VERSION 5.7 ;
  NOWIREEXTENSIONATPIN ON ;
  DIVIDERCHAR "/" ;
  BUSBITCHARS "[]" ;
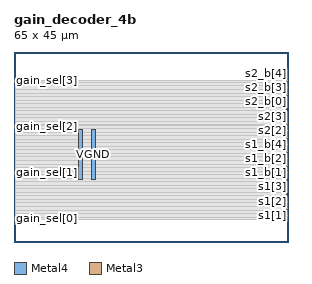
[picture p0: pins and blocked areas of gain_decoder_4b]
MACRO gain_decoder_4b
  CLASS BLOCK ;
  FOREIGN gain_decoder_4b ;
  ORIGIN 0.000 0.000 ;
  SIZE 65.000 BY 45.000 ;
  PIN VGND
    DIRECTION INOUT ;
    USE GROUND ;
    PORT
      LAYER Metal4 ;
        RECT 18.260 14.900 19.260 26.680 ;
    END
  END VGND
  PIN VPWR
    DIRECTION INOUT ;
    USE POWER ;
    PORT
      LAYER Metal4 ;
        RECT 15.260 14.900 16.260 26.680 ;
    END
  END VPWR
  PIN gain_sel[0]
    DIRECTION INPUT ;
    USE SIGNAL ;
    ANTENNAGATEAREA 0.180700 ;
    PORT
      LAYER Metal3 ;
        RECT 0.000 5.260 0.400 5.660 ;
    END
  END gain_sel[0]
  PIN gain_sel[1]
    DIRECTION INPUT ;
    USE SIGNAL ;
    ANTENNAGATEAREA 0.180700 ;
    PORT
      LAYER Metal3 ;
        RECT 0.000 16.180 0.400 16.580 ;
    END
  END gain_sel[1]
  PIN gain_sel[2]
    DIRECTION INPUT ;
    USE SIGNAL ;
    ANTENNAGATEAREA 0.180700 ;
    PORT
      LAYER Metal3 ;
        RECT 0.000 27.100 0.400 27.500 ;
    END
  END gain_sel[2]
  PIN gain_sel[3]
    DIRECTION INPUT ;
    USE SIGNAL ;
    ANTENNAGATEAREA 0.180700 ;
    PORT
      LAYER Metal3 ;
        RECT 0.000 38.020 0.400 38.420 ;
    END
  END gain_sel[3]
  PIN s1[0]
    DIRECTION OUTPUT ;
    USE SIGNAL ;
    ANTENNADIFFAREA 0.708600 ;
    PORT
      LAYER Metal3 ;
        RECT 64.600 6.100 65.000 6.500 ;
    END
  END s1[0]
  PIN s1[1]
    DIRECTION OUTPUT ;
    USE SIGNAL ;
    ANTENNADIFFAREA 0.708600 ;
    PORT
      LAYER Metal3 ;
        RECT 64.600 7.780 65.000 8.180 ;
    END
  END s1[1]
  PIN s1[2]
    DIRECTION OUTPUT ;
    USE SIGNAL ;
    ANTENNADIFFAREA 0.708600 ;
    PORT
      LAYER Metal3 ;
        RECT 64.600 9.460 65.000 9.860 ;
    END
  END s1[2]
  PIN s1[3]
    DIRECTION OUTPUT ;
    USE SIGNAL ;
    ANTENNADIFFAREA 0.708600 ;
    PORT
      LAYER Metal3 ;
        RECT 64.600 11.140 65.000 11.540 ;
    END
  END s1[3]
  PIN s1[4]
    DIRECTION OUTPUT ;
    USE SIGNAL ;
    ANTENNADIFFAREA 0.708600 ;
    PORT
      LAYER Metal3 ;
        RECT 64.600 12.820 65.000 13.220 ;
    END
  END s1[4]
  PIN s1_b[0]
    DIRECTION OUTPUT ;
    USE SIGNAL ;
    ANTENNADIFFAREA 0.708600 ;
    PORT
      LAYER Metal3 ;
        RECT 64.600 14.500 65.000 14.900 ;
    END
  END s1_b[0]
  PIN s1_b[1]
    DIRECTION OUTPUT ;
    USE SIGNAL ;
    ANTENNADIFFAREA 0.708600 ;
    PORT
      LAYER Metal3 ;
        RECT 64.600 16.180 65.000 16.580 ;
    END
  END s1_b[1]
  PIN s1_b[2]
    DIRECTION OUTPUT ;
    USE SIGNAL ;
    ANTENNADIFFAREA 0.708600 ;
    PORT
      LAYER Metal3 ;
        RECT 64.600 17.860 65.000 18.260 ;
    END
  END s1_b[2]
  PIN s1_b[3]
    DIRECTION OUTPUT ;
    USE SIGNAL ;
    ANTENNADIFFAREA 0.708600 ;
    PORT
      LAYER Metal3 ;
        RECT 64.600 19.540 65.000 19.940 ;
    END
  END s1_b[3]
  PIN s1_b[4]
    DIRECTION OUTPUT ;
    USE SIGNAL ;
    ANTENNADIFFAREA 0.708600 ;
    PORT
      LAYER Metal3 ;
        RECT 64.600 21.220 65.000 21.620 ;
    END
  END s1_b[4]
  PIN s2[0]
    DIRECTION OUTPUT ;
    USE SIGNAL ;
    ANTENNADIFFAREA 0.708600 ;
    PORT
      LAYER Metal3 ;
        RECT 64.600 22.900 65.000 23.300 ;
    END
  END s2[0]
  PIN s2[1]
    DIRECTION OUTPUT ;
    USE SIGNAL ;
    ANTENNADIFFAREA 0.708600 ;
    PORT
      LAYER Metal3 ;
        RECT 64.600 24.580 65.000 24.980 ;
    END
  END s2[1]
  PIN s2[2]
    DIRECTION OUTPUT ;
    USE SIGNAL ;
    ANTENNADIFFAREA 0.708600 ;
    PORT
      LAYER Metal3 ;
        RECT 64.600 26.260 65.000 26.660 ;
    END
  END s2[2]
  PIN s2[3]
    DIRECTION OUTPUT ;
    USE SIGNAL ;
    ANTENNADIFFAREA 0.708600 ;
    PORT
      LAYER Metal3 ;
        RECT 64.600 27.940 65.000 28.340 ;
    END
  END s2[3]
  PIN s2[4]
    DIRECTION OUTPUT ;
    USE SIGNAL ;
    ANTENNADIFFAREA 0.708600 ;
    PORT
      LAYER Metal3 ;
        RECT 64.600 29.620 65.000 30.020 ;
    END
  END s2[4]
  PIN s2_b[0]
    DIRECTION OUTPUT ;
    USE SIGNAL ;
    ANTENNADIFFAREA 0.708600 ;
    PORT
      LAYER Metal3 ;
        RECT 64.600 31.300 65.000 31.700 ;
    END
  END s2_b[0]
  PIN s2_b[1]
    DIRECTION OUTPUT ;
    USE SIGNAL ;
    ANTENNADIFFAREA 0.708600 ;
    PORT
      LAYER Metal3 ;
        RECT 64.600 32.980 65.000 33.380 ;
    END
  END s2_b[1]
  PIN s2_b[2]
    DIRECTION OUTPUT ;
    USE SIGNAL ;
    ANTENNADIFFAREA 0.708600 ;
    PORT
      LAYER Metal3 ;
        RECT 64.600 34.660 65.000 35.060 ;
    END
  END s2_b[2]
  PIN s2_b[3]
    DIRECTION OUTPUT ;
    USE SIGNAL ;
    ANTENNADIFFAREA 0.708600 ;
    PORT
      LAYER Metal3 ;
        RECT 64.600 36.340 65.000 36.740 ;
    END
  END s2_b[3]
  PIN s2_b[4]
    DIRECTION OUTPUT ;
    USE SIGNAL ;
    ANTENNADIFFAREA 0.708600 ;
    PORT
      LAYER Metal3 ;
        RECT 64.600 38.020 65.000 38.420 ;
    END
  END s2_b[4]
  OBS
      LAYER GatPoly ;
        RECT 5.760 14.970 59.040 26.610 ;
      LAYER Metal1 ;
        RECT 5.760 14.900 59.040 26.680 ;
      LAYER Metal2 ;
        RECT 6.135 5.315 59.145 38.365 ;
      LAYER Metal3 ;
        RECT 0.610 37.810 64.390 38.320 ;
        RECT 0.400 36.950 64.600 37.810 ;
        RECT 0.400 36.130 64.390 36.950 ;
        RECT 0.400 35.270 64.600 36.130 ;
        RECT 0.400 34.450 64.390 35.270 ;
        RECT 0.400 33.590 64.600 34.450 ;
        RECT 0.400 32.770 64.390 33.590 ;
        RECT 0.400 31.910 64.600 32.770 ;
        RECT 0.400 31.090 64.390 31.910 ;
        RECT 0.400 30.230 64.600 31.090 ;
        RECT 0.400 29.410 64.390 30.230 ;
        RECT 0.400 28.550 64.600 29.410 ;
        RECT 0.400 27.730 64.390 28.550 ;
        RECT 0.400 27.710 64.600 27.730 ;
        RECT 0.610 26.890 64.600 27.710 ;
        RECT 0.400 26.870 64.600 26.890 ;
        RECT 0.400 26.050 64.390 26.870 ;
        RECT 0.400 25.190 64.600 26.050 ;
        RECT 0.400 24.370 64.390 25.190 ;
        RECT 0.400 23.510 64.600 24.370 ;
        RECT 0.400 22.690 64.390 23.510 ;
        RECT 0.400 21.830 64.600 22.690 ;
        RECT 0.400 21.010 64.390 21.830 ;
        RECT 0.400 20.150 64.600 21.010 ;
        RECT 0.400 19.330 64.390 20.150 ;
        RECT 0.400 18.470 64.600 19.330 ;
        RECT 0.400 17.650 64.390 18.470 ;
        RECT 0.400 16.790 64.600 17.650 ;
        RECT 0.610 15.970 64.390 16.790 ;
        RECT 0.400 15.110 64.600 15.970 ;
        RECT 0.400 14.290 64.390 15.110 ;
        RECT 0.400 13.430 64.600 14.290 ;
        RECT 0.400 12.610 64.390 13.430 ;
        RECT 0.400 11.750 64.600 12.610 ;
        RECT 0.400 10.930 64.390 11.750 ;
        RECT 0.400 10.070 64.600 10.930 ;
        RECT 0.400 9.250 64.390 10.070 ;
        RECT 0.400 8.390 64.600 9.250 ;
        RECT 0.400 7.570 64.390 8.390 ;
        RECT 0.400 6.710 64.600 7.570 ;
        RECT 0.400 5.890 64.390 6.710 ;
        RECT 0.400 5.870 64.600 5.890 ;
        RECT 0.610 5.360 64.600 5.870 ;
  END
END gain_decoder_4b
END LIBRARY

